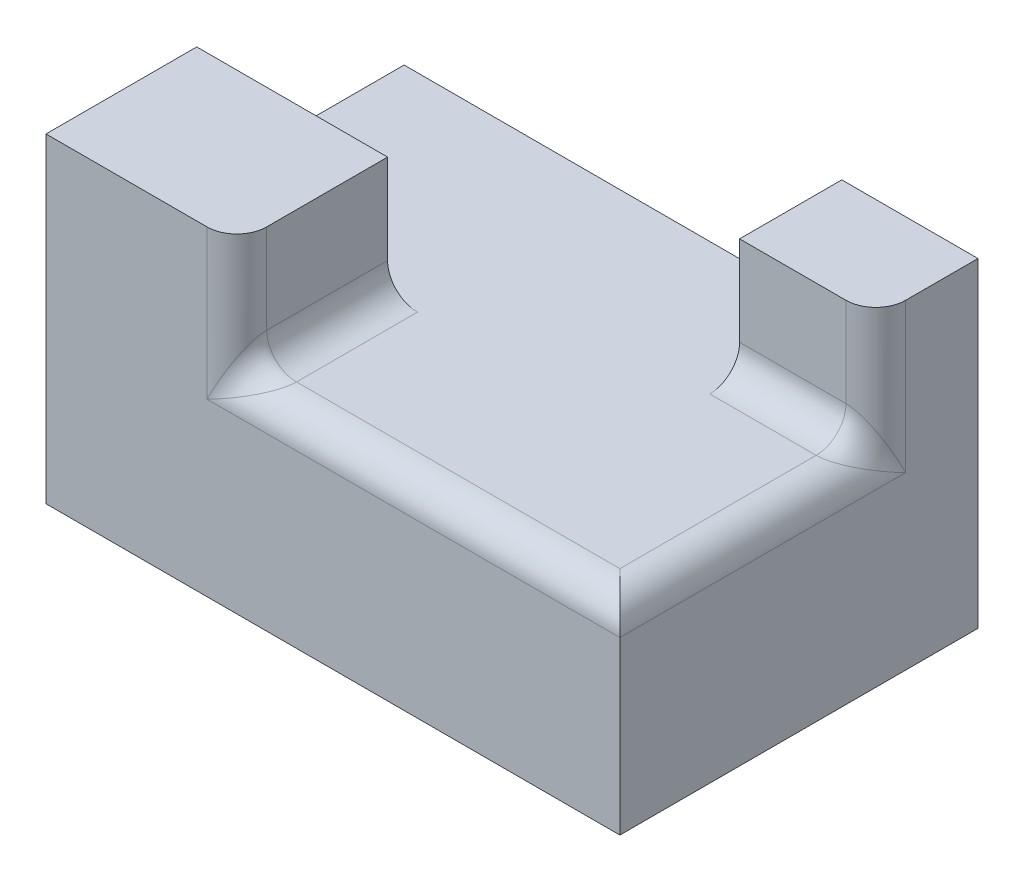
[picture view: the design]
ISO-10303-21;
HEADER;
FILE_DESCRIPTION(('STEP AP214'),'2;1');
FILE_NAME('part.step','',(''),(''),'','','');
FILE_SCHEMA(('AUTOMOTIVE_DESIGN { 1 0 10303 214 1 1 1 1 }'));
ENDSEC;
DATA;
#1=APPLICATION_CONTEXT('core data for automotive mechanical design processes');
#2=APPLICATION_PROTOCOL_DEFINITION('international standard','automotive_design',2000,#1);
#3=PRODUCT_CONTEXT('',#1,'mechanical');
#4=PRODUCT('Part','Part','',(#3));
#5=PRODUCT_RELATED_PRODUCT_CATEGORY('part','',(#4));
#6=PRODUCT_DEFINITION_FORMATION('','',#4);
#7=PRODUCT_DEFINITION_CONTEXT('part definition',#1,'design');
#8=PRODUCT_DEFINITION('design','',#6,#7);
#9=PRODUCT_DEFINITION_SHAPE('','',#8);
#10=(LENGTH_UNIT() NAMED_UNIT(*) SI_UNIT(.MILLI.,.METRE.));
#11=(NAMED_UNIT(*) PLANE_ANGLE_UNIT() SI_UNIT($,.RADIAN.));
#12=(NAMED_UNIT(*) SI_UNIT($,.STERADIAN.) SOLID_ANGLE_UNIT());
#13=UNCERTAINTY_MEASURE_WITH_UNIT(LENGTH_MEASURE(1.E-05),#10,'distance_accuracy_value','');
#14=(GEOMETRIC_REPRESENTATION_CONTEXT(3) GLOBAL_UNCERTAINTY_ASSIGNED_CONTEXT((#13)) GLOBAL_UNIT_ASSIGNED_CONTEXT((#10,
#11,#12)) REPRESENTATION_CONTEXT('',''));
#15=CARTESIAN_POINT('',(0.,0.,0.));
#16=DIRECTION('',(0.,0.,1.));
#17=DIRECTION('',(1.,0.,0.));
#18=AXIS2_PLACEMENT_3D('',#15,#16,#17);
#19=CARTESIAN_POINT('',(96.1490143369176,28.6618279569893,12.1202496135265));
#20=CARTESIAN_POINT('',(96.1490143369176,28.6618279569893,12.1202496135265));
#21=CARTESIAN_POINT('',(96.1490143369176,28.6618279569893,12.1202496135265));
#22=CARTESIAN_POINT('',(96.1490080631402,28.7707616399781,12.3381169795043));
#23=CARTESIAN_POINT('',(96.1490377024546,28.8252281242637,12.283649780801));
#24=CARTESIAN_POINT('',(96.1490080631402,28.879695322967,12.2291832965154));
#25=CARTESIAN_POINT('',(96.1454544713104,28.8796796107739,12.5559529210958));
#26=CARTESIAN_POINT('',(96.1418871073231,28.9887210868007,12.447142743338));
#27=CARTESIAN_POINT('',(96.1454544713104,29.0975312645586,12.3381012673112));
#28=CARTESIAN_POINT('',(96.1312103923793,29.0972907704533,12.9911752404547));
#29=CARTESIAN_POINT('',(96.1134165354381,29.3144399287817,12.772861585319));
#30=CARTESIAN_POINT('',(96.1312103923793,29.5327535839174,12.5557124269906));
#31=CARTESIAN_POINT('',(96.1205193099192,29.2059839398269,13.2085615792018));
#32=CARTESIAN_POINT('',(96.0920548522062,29.4768961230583,12.9353177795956));
#33=CARTESIAN_POINT('',(96.1205193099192,29.7501399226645,12.6644055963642));
#34=CARTESIAN_POINT('',(96.0779288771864,29.5294979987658,13.8555896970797));
#35=CARTESIAN_POINT('',(96.0070926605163,29.958646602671,13.4170682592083));
#36=CARTESIAN_POINT('',(96.0779288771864,30.3971680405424,12.9879196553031));
#37=CARTESIAN_POINT('',(96.0355125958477,29.7436796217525,14.283952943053));
#38=CARTESIAN_POINT('',(95.9223415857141,30.2752082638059,13.7336299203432));
#39=CARTESIAN_POINT('',(96.0355125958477,30.8255312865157,13.2021012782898));
#40=CARTESIAN_POINT('',(95.9227282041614,30.1646067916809,15.1258072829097));
#41=CARTESIAN_POINT('',(95.7008351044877,30.8841688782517,14.342590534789));
#42=CARTESIAN_POINT('',(95.9227282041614,31.6673856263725,13.6230284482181));
#43=CARTESIAN_POINT('',(95.852840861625,30.3714168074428,15.5394273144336));
#44=CARTESIAN_POINT('',(95.5637556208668,31.1783980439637,14.636819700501));
#45=CARTESIAN_POINT('',(95.852840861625,32.0810056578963,13.8298384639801));
#46=CARTESIAN_POINT('',(95.6860629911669,30.7740522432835,16.344698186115));
#47=CARTESIAN_POINT('',(95.244452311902,31.7320304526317,15.190452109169));
#48=CARTESIAN_POINT('',(95.6860629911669,32.8862765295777,14.2324738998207));
#49=CARTESIAN_POINT('',(95.5898800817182,30.9700227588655,16.7366392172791));
#50=CARTESIAN_POINT('',(95.0617453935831,31.9932055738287,15.451627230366));
#51=CARTESIAN_POINT('',(95.5898800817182,33.2782175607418,14.4284444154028));
#52=CARTESIAN_POINT('',(95.3719274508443,31.3475279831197,17.4916496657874));
#53=CARTESIAN_POINT('',(94.661515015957,32.4707340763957,15.9291557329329));
#54=CARTESIAN_POINT('',(95.3719274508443,34.0332280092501,14.805949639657));
#55=CARTESIAN_POINT('',(95.2510696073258,31.5293236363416,17.8552409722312));
#56=CARTESIAN_POINT('',(94.4433664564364,32.6887553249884,16.1471769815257));
#57=CARTESIAN_POINT('',(95.2510696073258,34.3968193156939,14.9877452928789));
#58=CARTESIAN_POINT('',(94.985632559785,31.8752478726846,18.5470894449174));
#59=CARTESIAN_POINT('',(93.9867474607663,33.0715758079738,16.529997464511));
#60=CARTESIAN_POINT('',(94.985632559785,35.0886677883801,15.3336695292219));
#61=CARTESIAN_POINT('',(94.8421290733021,32.0397852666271,18.8761642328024));
#62=CARTESIAN_POINT('',(93.7475519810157,33.2378779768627,16.6962996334));
#63=CARTESIAN_POINT('',(94.8421290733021,35.4177425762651,15.4982069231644));
#64=CARTESIAN_POINT('',(94.5336806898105,32.348225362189,19.4930444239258));
#65=CARTESIAN_POINT('',(93.2679895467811,33.5118870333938,16.9703086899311));
#66=CARTESIAN_POINT('',(94.5336806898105,36.0346227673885,15.8066470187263));
#67=CARTESIAN_POINT('',(94.3699096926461,32.4927085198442,19.7820107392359));
#68=CARTESIAN_POINT('',(93.0268733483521,33.6208675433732,17.0792891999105));
#69=CARTESIAN_POINT('',(94.3699096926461,36.3235890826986,15.9511301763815));
#70=CARTESIAN_POINT('',(94.0236930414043,32.7583729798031,20.3133396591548));
#71=CARTESIAN_POINT('',(92.5666913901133,33.7802352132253,17.2386568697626));
#72=CARTESIAN_POINT('',(94.0236930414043,36.8549180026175,16.2167946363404));
#73=CARTESIAN_POINT('',(93.8424176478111,32.8803097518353,20.5572132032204));
#74=CARTESIAN_POINT('',(92.3469605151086,33.831617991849,17.2900396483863));
#75=CARTESIAN_POINT('',(93.8424176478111,37.0987915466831,16.3387314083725));
#76=CARTESIAN_POINT('',(93.4641525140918,33.0986694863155,20.9939326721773));
#77=CARTESIAN_POINT('',(91.9539994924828,33.8839523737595,17.3423740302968));
#78=CARTESIAN_POINT('',(93.4641525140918,37.53551101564,16.5570911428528));
#79=CARTESIAN_POINT('',(93.2682103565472,33.1959814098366,21.1885565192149));
#80=CARTESIAN_POINT('',(91.7802865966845,33.8856184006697,17.344040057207));
#81=CARTESIAN_POINT('',(93.2682103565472,37.7301348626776,16.6544030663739));
#82=CARTESIAN_POINT('',(92.9634821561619,33.3222155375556,21.4410247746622));
#83=CARTESIAN_POINT('',(91.5679602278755,33.8642822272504,17.3227038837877));
#84=CARTESIAN_POINT('',(92.9634821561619,37.9826031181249,16.7806371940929));
#85=CARTESIAN_POINT('',(92.862258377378,33.3604151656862,21.517424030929));
#86=CARTESIAN_POINT('',(91.5057132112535,33.853419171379,17.3118408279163));
#87=CARTESIAN_POINT('',(92.862258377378,38.0590023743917,16.8188368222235));
#88=CARTESIAN_POINT('',(92.6556569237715,33.430675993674,21.6579456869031));
#89=CARTESIAN_POINT('',(91.3965943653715,33.8268596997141,17.2852813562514));
#90=CARTESIAN_POINT('',(92.6556569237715,38.1995240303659,16.8890976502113));
#91=CARTESIAN_POINT('',(92.5502812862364,33.4627401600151,21.7220740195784));
#92=CARTESIAN_POINT('',(91.3499908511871,33.8111282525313,17.2695499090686));
#93=CARTESIAN_POINT('',(92.5502812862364,38.2636523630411,16.9211618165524));
#94=CARTESIAN_POINT('',(92.3390935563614,33.5193284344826,21.8352505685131));
#95=CARTESIAN_POINT('',(91.2737685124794,33.7785309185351,17.2369525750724));
#96=CARTESIAN_POINT('',(92.3390935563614,38.3768289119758,16.9777500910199));
#97=CARTESIAN_POINT('',(92.2333856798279,33.5440467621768,21.8846872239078));
#98=CARTESIAN_POINT('',(91.2439084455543,33.7617235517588,17.2201452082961));
#99=CARTESIAN_POINT('',(92.2333856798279,38.4262655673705,17.0024684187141));
#100=CARTESIAN_POINT('',(92.0193127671,33.5867119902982,21.9700176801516));
#101=CARTESIAN_POINT('',(91.1978030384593,33.7298203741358,17.1882420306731));
#102=CARTESIAN_POINT('',(92.0193127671,38.5115960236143,17.0451336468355));
#103=CARTESIAN_POINT('',(91.910949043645,33.6046621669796,22.005918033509));
#104=CARTESIAN_POINT('',(91.1817160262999,33.7147753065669,17.1731969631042));
#105=CARTESIAN_POINT('',(91.910949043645,38.5474963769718,17.0630838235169));
#106=CARTESIAN_POINT('',(91.6941005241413,33.6332107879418,22.0630152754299));
#107=CARTESIAN_POINT('',(91.1601582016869,33.6895473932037,17.147969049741));
#108=CARTESIAN_POINT('',(91.6941005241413,38.6045936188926,17.0916324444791));
#109=CARTESIAN_POINT('',(91.5856457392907,33.6439228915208,22.0844394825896));
#110=CARTESIAN_POINT('',(91.1546045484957,33.6793472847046,17.1377689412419));
#111=CARTESIAN_POINT('',(91.5856457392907,38.6260178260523,17.1023445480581));
#112=CARTESIAN_POINT('',(91.3677987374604,33.6582314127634,22.1130565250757));
#113=CARTESIAN_POINT('',(91.1490230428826,33.66546856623,17.1238902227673));
#114=CARTESIAN_POINT('',(91.3677987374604,38.6546348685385,17.1166530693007));
#115=CARTESIAN_POINT('',(91.258406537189,33.6618279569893,22.1202496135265));
#116=CARTESIAN_POINT('',(91.149018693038,33.6618279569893,17.1202496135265));
#117=CARTESIAN_POINT('',(91.258406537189,38.6618279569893,17.1202496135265));
#118=CARTESIAN_POINT('',(91.0396221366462,33.6618279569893,22.1202496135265));
#119=CARTESIAN_POINT('',(91.1490099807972,33.6618279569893,17.1202496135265));
#120=CARTESIAN_POINT('',(91.0396221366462,38.6618279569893,17.1202496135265));
#121=CARTESIAN_POINT('',(90.9302299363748,33.6582314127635,22.1130565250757));
#122=CARTESIAN_POINT('',(91.1490056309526,33.66546856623,17.1238902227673));
#123=CARTESIAN_POINT('',(90.9302299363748,38.6546348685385,17.1166530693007));
#124=CARTESIAN_POINT('',(90.7123829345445,33.6439228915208,22.0844394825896));
#125=CARTESIAN_POINT('',(91.1434241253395,33.6793472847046,17.1377689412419));
#126=CARTESIAN_POINT('',(90.7123829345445,38.6260178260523,17.1023445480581));
#127=CARTESIAN_POINT('',(90.6039281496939,33.6332107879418,22.0630152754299));
#128=CARTESIAN_POINT('',(91.1378704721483,33.6895473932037,17.147969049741));
#129=CARTESIAN_POINT('',(90.6039281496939,38.6045936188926,17.0916324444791));
#130=CARTESIAN_POINT('',(90.3870796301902,33.6046621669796,22.005918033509));
#131=CARTESIAN_POINT('',(91.1163126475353,33.7147753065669,17.1731969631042));
#132=CARTESIAN_POINT('',(90.3870796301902,38.5474963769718,17.0630838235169));
#133=CARTESIAN_POINT('',(90.2787159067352,33.5867119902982,21.9700176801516));
#134=CARTESIAN_POINT('',(91.1002256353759,33.7298203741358,17.1882420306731));
#135=CARTESIAN_POINT('',(90.2787159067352,38.5115960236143,17.0451336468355));
#136=CARTESIAN_POINT('',(90.0646429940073,33.5440467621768,21.8846872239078));
#137=CARTESIAN_POINT('',(91.0541202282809,33.7617235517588,17.2201452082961));
#138=CARTESIAN_POINT('',(90.0646429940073,38.4262655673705,17.0024684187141));
#139=CARTESIAN_POINT('',(89.9589351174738,33.5193284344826,21.8352505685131));
#140=CARTESIAN_POINT('',(91.0242601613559,33.7785309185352,17.2369525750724));
#141=CARTESIAN_POINT('',(89.9589351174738,38.3768289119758,16.9777500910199));
#142=CARTESIAN_POINT('',(89.7477473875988,33.4627401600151,21.7220740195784));
#143=CARTESIAN_POINT('',(90.9480378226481,33.8111282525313,17.2695499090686));
#144=CARTESIAN_POINT('',(89.7477473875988,38.2636523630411,16.9211618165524));
#145=CARTESIAN_POINT('',(89.6423717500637,33.430675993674,21.6579456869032));
#146=CARTESIAN_POINT('',(90.9014343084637,33.8268596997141,17.2852813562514));
#147=CARTESIAN_POINT('',(89.6423717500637,38.1995240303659,16.8890976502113));
#148=CARTESIAN_POINT('',(89.4357702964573,33.3604151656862,21.517424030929));
#149=CARTESIAN_POINT('',(90.7923154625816,33.853419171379,17.3118408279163));
#150=CARTESIAN_POINT('',(89.4357702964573,38.0590023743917,16.8188368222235));
#151=CARTESIAN_POINT('',(89.3345465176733,33.3222155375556,21.4410247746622));
#152=CARTESIAN_POINT('',(90.7300684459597,33.8642822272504,17.3227038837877));
#153=CARTESIAN_POINT('',(89.3345465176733,37.9826031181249,16.7806371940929));
#154=CARTESIAN_POINT('',(89.029818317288,33.1959814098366,21.1885565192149));
#155=CARTESIAN_POINT('',(90.5177420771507,33.8856184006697,17.344040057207));
#156=CARTESIAN_POINT('',(89.029818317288,37.7301348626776,16.6544030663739));
#157=CARTESIAN_POINT('',(88.8338761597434,33.0986694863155,20.9939326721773));
#158=CARTESIAN_POINT('',(90.3440291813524,33.8839523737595,17.3423740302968));
#159=CARTESIAN_POINT('',(88.8338761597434,37.53551101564,16.5570911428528));
#160=CARTESIAN_POINT('',(88.4556110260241,32.8803097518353,20.5572132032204));
#161=CARTESIAN_POINT('',(89.9510681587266,33.831617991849,17.2900396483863));
#162=CARTESIAN_POINT('',(88.4556110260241,37.0987915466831,16.3387314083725));
#163=CARTESIAN_POINT('',(88.2743356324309,32.7583729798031,20.3133396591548));
#164=CARTESIAN_POINT('',(89.7313372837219,33.7802352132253,17.2386568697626));
#165=CARTESIAN_POINT('',(88.2743356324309,36.8549180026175,16.2167946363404));
#166=CARTESIAN_POINT('',(87.9281189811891,32.4927085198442,19.7820107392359));
#167=CARTESIAN_POINT('',(89.2711553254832,33.6208675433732,17.0792891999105));
#168=CARTESIAN_POINT('',(87.9281189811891,36.3235890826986,15.9511301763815));
#169=CARTESIAN_POINT('',(87.7643479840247,32.348225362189,19.4930444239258));
#170=CARTESIAN_POINT('',(89.0300391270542,33.5118870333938,16.9703086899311));
#171=CARTESIAN_POINT('',(87.7643479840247,36.0346227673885,15.8066470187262));
#172=CARTESIAN_POINT('',(87.4558996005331,32.0397852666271,18.8761642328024));
#173=CARTESIAN_POINT('',(88.5504766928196,33.2378779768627,16.6962996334));
#174=CARTESIAN_POINT('',(87.4558996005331,35.4177425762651,15.4982069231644));
#175=CARTESIAN_POINT('',(87.3123961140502,31.8752478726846,18.5470894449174));
#176=CARTESIAN_POINT('',(88.3112812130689,33.0715758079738,16.529997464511));
#177=CARTESIAN_POINT('',(87.3123961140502,35.0886677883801,15.3336695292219));
#178=CARTESIAN_POINT('',(87.0469590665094,31.5293236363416,17.8552409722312));
#179=CARTESIAN_POINT('',(87.8546622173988,32.6887553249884,16.1471769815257));
#180=CARTESIAN_POINT('',(87.0469590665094,34.3968193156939,14.9877452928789));
#181=CARTESIAN_POINT('',(86.9261012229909,31.3475279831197,17.4916496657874));
#182=CARTESIAN_POINT('',(87.6365136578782,32.4707340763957,15.929155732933));
#183=CARTESIAN_POINT('',(86.9261012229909,34.0332280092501,14.805949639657));
#184=CARTESIAN_POINT('',(86.708148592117,30.9700227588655,16.7366392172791));
#185=CARTESIAN_POINT('',(87.2362832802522,31.9932055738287,15.451627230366));
#186=CARTESIAN_POINT('',(86.708148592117,33.2782175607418,14.4284444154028));
#187=CARTESIAN_POINT('',(86.6119656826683,30.7740522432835,16.344698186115));
#188=CARTESIAN_POINT('',(87.0535763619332,31.7320304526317,15.190452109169));
#189=CARTESIAN_POINT('',(86.6119656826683,32.8862765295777,14.2324738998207));
#190=CARTESIAN_POINT('',(86.4451878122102,30.3714168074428,15.5394273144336));
#191=CARTESIAN_POINT('',(86.7342730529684,31.1783980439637,14.636819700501));
#192=CARTESIAN_POINT('',(86.4451878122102,32.0810056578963,13.8298384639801));
#193=CARTESIAN_POINT('',(86.3753004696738,30.1646067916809,15.1258072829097));
#194=CARTESIAN_POINT('',(86.5971935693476,30.8841688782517,14.342590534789));
#195=CARTESIAN_POINT('',(86.3753004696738,31.6673856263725,13.6230284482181));
#196=CARTESIAN_POINT('',(86.2625160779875,29.7436796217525,14.283952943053));
#197=CARTESIAN_POINT('',(86.3756870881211,30.2752082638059,13.7336299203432));
#198=CARTESIAN_POINT('',(86.2625160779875,30.8255312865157,13.2021012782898));
#199=CARTESIAN_POINT('',(86.2200997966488,29.5294979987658,13.8555896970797));
#200=CARTESIAN_POINT('',(86.2909360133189,29.958646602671,13.4170682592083));
#201=CARTESIAN_POINT('',(86.2200997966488,30.3971680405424,12.9879196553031));
#202=CARTESIAN_POINT('',(86.177509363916,29.2059839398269,13.2085615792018));
#203=CARTESIAN_POINT('',(86.205973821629,29.4768961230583,12.9353177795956));
#204=CARTESIAN_POINT('',(86.177509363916,29.7501399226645,12.6644055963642));
#205=CARTESIAN_POINT('',(86.1668182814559,29.0972907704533,12.9911752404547));
#206=CARTESIAN_POINT('',(86.1846121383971,29.3144399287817,12.772861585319));
#207=CARTESIAN_POINT('',(86.1668182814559,29.5327535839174,12.5557124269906));
#208=CARTESIAN_POINT('',(86.1525742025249,28.8796796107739,12.5559529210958));
#209=CARTESIAN_POINT('',(86.156141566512,28.9887210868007,12.447142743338));
#210=CARTESIAN_POINT('',(86.1525742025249,29.0975312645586,12.3381012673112));
#211=CARTESIAN_POINT('',(86.149020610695,28.7707616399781,12.3381169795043));
#212=CARTESIAN_POINT('',(86.1489909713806,28.8252281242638,12.283649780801));
#213=CARTESIAN_POINT('',(86.149020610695,28.879695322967,12.2291832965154));
#214=CARTESIAN_POINT('',(86.1490143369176,28.6618279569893,12.1202496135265));
#215=CARTESIAN_POINT('',(86.1490143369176,28.6618279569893,12.1202496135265));
#216=CARTESIAN_POINT('',(86.1490143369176,28.6618279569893,12.1202496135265));
#217=(BOUNDED_SURFACE() B_SPLINE_SURFACE(3,2,((#19,#20,#21),(#22,#23,#24),(#25,#26,#27),(#28,
#29,#30),(#31,#32,#33),(#34,#35,#36),(#37,#38,#39),(#40,#41,#42),(#43,#44,#45),(#46,#47,#48),
(#49,#50,#51),(#52,#53,#54),(#55,#56,#57),(#58,#59,#60),(#61,#62,#63),(#64,#65,#66),(#67,#68,
#69),(#70,#71,#72),(#73,#74,#75),(#76,#77,#78),(#79,#80,#81),(#82,#83,#84),(#85,#86,#87),(#88,
#89,#90),(#91,#92,#93),(#94,#95,#96),(#97,#98,#99),(#100,#101,#102),(#103,#104,#105),(#106,#107,
#108),(#109,#110,#111),(#112,#113,#114),(#115,#116,#117),(#118,#119,#120),(#121,#122,#123),
(#124,#125,#126),(#127,#128,#129),(#130,#131,#132),(#133,#134,#135),(#136,#137,#138),(#139,#140,
#141),(#142,#143,#144),(#145,#146,#147),(#148,#149,#150),(#151,#152,#153),(#154,#155,#156),
(#157,#158,#159),(#160,#161,#162),(#163,#164,#165),(#166,#167,#168),(#169,#170,#171),(#172,#173,
#174),(#175,#176,#177),(#178,#179,#180),(#181,#182,#183),(#184,#185,#186),(#187,#188,#189),
(#190,#191,#192),(#193,#194,#195),(#196,#197,#198),(#199,#200,#201),(#202,#203,#204),(#205,#206,
#207),(#208,#209,#210),(#211,#212,#213),(#214,#215,#216)),.UNSPECIFIED.,.F.,.F.,
.F.) B_SPLINE_SURFACE_WITH_KNOTS((4,2,2,2,2,2,2,2,2,2,2,2,2,2,2,2,2,2,2,2,2,2,2,2,2,2,2,2,2,2,2,
2,4),(3,3),(0.,0.924160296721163,1.84839768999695,3.68059127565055,5.48205356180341,
7.23913791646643,8.94029416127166,10.5768174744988,12.1436214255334,13.6400005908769,
15.0702934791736,15.7580538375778,16.4454808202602,17.1126662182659,17.7795282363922,
18.4356587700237,19.0917776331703,19.7478964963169,20.4040270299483,21.0708890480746,
21.7380744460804,22.4255014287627,23.1132617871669,24.5435546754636,26.0399338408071,
27.6067377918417,29.2432611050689,30.9444173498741,32.7015017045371,34.50296399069,
36.3351575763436,37.2593949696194,38.1835552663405),(0.,1.),
.UNSPECIFIED.) GEOMETRIC_REPRESENTATION_ITEM() RATIONAL_B_SPLINE_SURFACE(((1.,1.,1.),(1.,
0.999999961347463,1.),(1.,0.999643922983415,1.),(1.,0.998220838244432,1.),(1.,0.9971537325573,
1.),(1.,0.992912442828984,1.),(1.,0.988698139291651,1.),(1.,0.97761667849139,1.),(1.,
0.970795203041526,1.),(1.,0.954789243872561,1.),(1.,0.945667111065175,1.),(1.,0.925487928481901,
1.),(1.,0.914501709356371,1.),(1.,0.891170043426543,1.),(1.,0.878892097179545,1.),(1.,
0.853706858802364,1.),(1.,0.840848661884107,1.),(1.,0.815387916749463,1.),(1.,0.802799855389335,
1.),(1.,0.778879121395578,1.),(1.,0.767515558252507,1.),(1.,0.752114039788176,1.),(1.,
0.747335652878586,1.),(1.,0.738380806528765,1.),(1.,0.734204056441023,1.),(1.,0.726720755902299,
1.),(1.,0.723392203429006,1.),(1.,0.717584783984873,1.),(1.,0.715105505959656,1.),(1.,
0.711136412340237,1.),(1.,0.709631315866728,1.),(1.,0.70761650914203,1.),(1.,0.707106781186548,
1.),(1.,0.707106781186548,1.),(1.,0.70761650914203,1.),(1.,0.709631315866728,1.),(1.,
0.711136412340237,1.),(1.,0.715105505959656,1.),(1.,0.717584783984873,1.),(1.,0.723392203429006,
1.),(1.,0.726720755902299,1.),(1.,0.734204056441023,1.),(1.,0.738380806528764,1.),(1.,
0.747335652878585,1.),(1.,0.752114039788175,1.),(1.,0.767515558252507,1.),(1.,0.778879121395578,
1.),(1.,0.802799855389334,1.),(1.,0.815387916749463,1.),(1.,0.840848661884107,1.),(1.,
0.853706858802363,1.),(1.,0.878892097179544,1.),(1.,0.891170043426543,1.),(1.,0.914501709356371,
1.),(1.,0.925487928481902,1.),(1.,0.945667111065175,1.),(1.,0.954789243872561,1.),(1.,
0.970795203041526,1.),(1.,0.97761667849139,1.),(1.,0.988698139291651,1.),(1.,0.992912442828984,
1.),(1.,0.9971537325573,1.),(1.,0.998220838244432,1.),(1.,0.999643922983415,1.),(1.,
0.999999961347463,1.),(1.,1.,1.))) REPRESENTATION_ITEM('') SURFACE());
#218=CARTESIAN_POINT('',(91.1490143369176,38.6618279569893,22.1202496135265));
#219=DIRECTION('',(-1.,0.,0.));
#220=DIRECTION('',(0.,0.,1.));
#221=AXIS2_PLACEMENT_3D('',#218,#219,#220);
#222=CIRCLE('',#221,5.);
#223=CARTESIAN_POINT('',(91.1490143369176,38.6618279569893,17.1202496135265));
#224=VERTEX_POINT('',#223);
#225=CARTESIAN_POINT('',(91.1490143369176,33.6618279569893,22.1202496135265));
#226=VERTEX_POINT('',#225);
#227=EDGE_CURVE('E103',#224,#226,#222,.T.);
#228=ORIENTED_EDGE('',*,*,#227,.T.);
#229=CARTESIAN_POINT('',(91.1490143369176,28.6618279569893,12.1202496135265));
#230=DIRECTION('',(0.,0.894427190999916,-0.447213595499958));
#231=DIRECTION('',(0.,-0.447213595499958,-0.894427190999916));
#232=AXIS2_PLACEMENT_3D('',#229,#230,#231);
#233=ELLIPSE('',#232,11.1803398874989,5.);
#234=CARTESIAN_POINT('',(96.1490143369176,28.6618279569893,12.1202496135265));
#235=VERTEX_POINT('',#234);
#236=EDGE_CURVE('E109',#235,#226,#233,.F.);
#237=ORIENTED_EDGE('',*,*,#236,.F.);
#238=CARTESIAN_POINT('',(91.1490143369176,28.6618279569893,12.1202496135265));
#239=DIRECTION('',(0.,0.447213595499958,-0.894427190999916));
#240=DIRECTION('',(0.,-0.894427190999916,-0.447213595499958));
#241=AXIS2_PLACEMENT_3D('',#238,#239,#240);
#242=ELLIPSE('',#241,11.1803398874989,5.);
#243=EDGE_CURVE('E115',#224,#235,#242,.T.);
#244=ORIENTED_EDGE('',*,*,#243,.F.);
#245=EDGE_LOOP('',(#228,#237,#244));
#246=FACE_BOUND('',#245,.T.);
#247=ADVANCED_FACE('F32',(#246),#217,.F.);
#248=CARTESIAN_POINT('',(0.,33.6618279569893,60.));
#249=DIRECTION('',(0.,-1.,0.));
#250=DIRECTION('',(0.,0.,-1.));
#251=AXIS2_PLACEMENT_3D('',#248,#249,#250);
#252=PLANE('',#251);
#253=DIRECTION('',(0.,0.,-1.));
#254=VECTOR('',#253,1.);
#255=CARTESIAN_POINT('',(91.1490143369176,33.6618279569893,60.));
#256=LINE('',#255,#254);
#257=CARTESIAN_POINT('',(91.1490143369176,33.6618279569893,55.));
#258=VERTEX_POINT('',#257);
#259=EDGE_CURVE('E83',#258,#226,#256,.T.);
#260=ORIENTED_EDGE('',*,*,#259,.T.);
#261=DIRECTION('',(1.,0.,0.));
#262=VECTOR('',#261,1.);
#263=CARTESIAN_POINT('',(73.3247964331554,33.6618279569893,22.1202496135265));
#264=LINE('',#263,#262);
#265=CARTESIAN_POINT('',(73.3247964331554,33.6618279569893,22.1202496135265));
#266=VERTEX_POINT('',#265);
#267=EDGE_CURVE('E88',#226,#266,#264,.F.);
#268=ORIENTED_EDGE('',*,*,#267,.T.);
#269=DIRECTION('',(0.,0.,1.));
#270=VECTOR('',#269,1.);
#271=CARTESIAN_POINT('',(73.3247964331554,33.6618279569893,0.));
#272=LINE('',#271,#270);
#273=CARTESIAN_POINT('',(73.3247964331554,33.6618279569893,0.));
#274=VERTEX_POINT('',#273);
#275=EDGE_CURVE('E213',#274,#266,#272,.T.);
#276=ORIENTED_EDGE('',*,*,#275,.F.);
#277=DIRECTION('',(-1.,0.,0.));
#278=VECTOR('',#277,1.);
#279=CARTESIAN_POINT('',(0.,33.6618279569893,0.));
#280=LINE('',#279,#278);
#281=CARTESIAN_POINT('',(0.,33.6618279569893,0.));
#282=VERTEX_POINT('',#281);
#283=EDGE_CURVE('E355',#274,#282,#280,.T.);
#284=ORIENTED_EDGE('',*,*,#283,.T.);
#285=DIRECTION('',(0.,0.,-1.));
#286=VECTOR('',#285,1.);
#287=CARTESIAN_POINT('',(0.,33.6618279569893,60.));
#288=LINE('',#287,#286);
#289=CARTESIAN_POINT('',(0.,33.6618279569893,34.7454000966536));
#290=VERTEX_POINT('',#289);
#291=EDGE_CURVE('E250',#290,#282,#288,.T.);
#292=ORIENTED_EDGE('',*,*,#291,.F.);
#293=DIRECTION('',(-1.,0.,0.));
#294=VECTOR('',#293,1.);
#295=CARTESIAN_POINT('',(0.,33.6618279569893,34.7454000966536));
#296=LINE('',#295,#294);
#297=CARTESIAN_POINT('',(36.9746669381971,33.6618279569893,34.7454000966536));
#298=VERTEX_POINT('',#297);
#299=EDGE_CURVE('E228',#298,#290,#296,.T.);
#300=ORIENTED_EDGE('',*,*,#299,.F.);
#301=DIRECTION('',(0.,0.,-1.));
#302=VECTOR('',#301,1.);
#303=CARTESIAN_POINT('',(36.9746669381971,33.6618279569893,60.));
#304=LINE('',#303,#302);
#305=CARTESIAN_POINT('',(36.9746669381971,33.6618279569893,55.));
#306=VERTEX_POINT('',#305);
#307=EDGE_CURVE('E264',#298,#306,#304,.F.);
#308=ORIENTED_EDGE('',*,*,#307,.T.);
#309=DIRECTION('',(-1.,0.,0.));
#310=VECTOR('',#309,1.);
#311=CARTESIAN_POINT('',(0.,33.6618279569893,55.));
#312=LINE('',#311,#310);
#313=EDGE_CURVE('E91',#306,#258,#312,.F.);
#314=ORIENTED_EDGE('',*,*,#313,.T.);
#315=EDGE_LOOP('',(#260,#268,#276,#284,#292,#300,#308,#314));
#316=FACE_BOUND('',#315,.T.);
#317=ADVANCED_FACE('F85',(#316),#252,.F.);
#318=CARTESIAN_POINT('',(0.,0.,60.));
#319=DIRECTION('',(1.,0.,0.));
#320=DIRECTION('',(0.,0.,-1.));
#321=AXIS2_PLACEMENT_3D('',#318,#319,#320);
#322=PLANE('',#321);
#323=DIRECTION('',(0.,-1.,0.));
#324=VECTOR('',#323,1.);
#325=CARTESIAN_POINT('',(0.,0.,0.));
#326=LINE('',#325,#324);
#327=CARTESIAN_POINT('',(0.,0.,0.));
#328=VERTEX_POINT('',#327);
#329=EDGE_CURVE('E340',#282,#328,#326,.T.);
#330=ORIENTED_EDGE('',*,*,#329,.T.);
#331=DIRECTION('',(0.,0.,-1.));
#332=VECTOR('',#331,1.);
#333=CARTESIAN_POINT('',(0.,0.,60.));
#334=LINE('',#333,#332);
#335=CARTESIAN_POINT('',(0.,0.,60.));
#336=VERTEX_POINT('',#335);
#337=EDGE_CURVE('E260',#336,#328,#334,.T.);
#338=ORIENTED_EDGE('',*,*,#337,.F.);
#339=DIRECTION('',(0.,-1.,0.));
#340=VECTOR('',#339,1.);
#341=CARTESIAN_POINT('',(0.,0.,60.));
#342=LINE('',#341,#340);
#343=CARTESIAN_POINT('',(0.,53.6618279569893,60.));
#344=VERTEX_POINT('',#343);
#345=EDGE_CURVE('E356',#344,#336,#342,.T.);
#346=ORIENTED_EDGE('',*,*,#345,.F.);
#347=DIRECTION('',(0.,0.,1.));
#348=VECTOR('',#347,1.);
#349=CARTESIAN_POINT('',(0.,53.6618279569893,60.));
#350=LINE('',#349,#348);
#351=CARTESIAN_POINT('',(0.,53.6618279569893,34.7454000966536));
#352=VERTEX_POINT('',#351);
#353=EDGE_CURVE('E229',#352,#344,#350,.T.);
#354=ORIENTED_EDGE('',*,*,#353,.F.);
#355=DIRECTION('',(0.,-1.,0.));
#356=VECTOR('',#355,1.);
#357=CARTESIAN_POINT('',(0.,53.6618279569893,34.7454000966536));
#358=LINE('',#357,#356);
#359=EDGE_CURVE('E241',#352,#290,#358,.T.);
#360=ORIENTED_EDGE('',*,*,#359,.T.);
#361=ORIENTED_EDGE('',*,*,#291,.T.);
#362=EDGE_LOOP('',(#330,#338,#346,#354,#360,#361));
#363=FACE_BOUND('',#362,.T.);
#364=ADVANCED_FACE('F141',(#363),#322,.F.);
#365=CARTESIAN_POINT('',(0.,0.,60.));
#366=DIRECTION('',(0.,1.,0.));
#367=DIRECTION('',(0.,0.,1.));
#368=AXIS2_PLACEMENT_3D('',#365,#366,#367);
#369=PLANE('',#368);
#370=DIRECTION('',(1.,0.,0.));
#371=VECTOR('',#370,1.);
#372=CARTESIAN_POINT('',(0.,0.,0.));
#373=LINE('',#372,#371);
#374=CARTESIAN_POINT('',(96.1490143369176,0.,0.));
#375=VERTEX_POINT('',#374);
#376=EDGE_CURVE('E342',#328,#375,#373,.T.);
#377=ORIENTED_EDGE('',*,*,#376,.T.);
#378=DIRECTION('',(0.,0.,-1.));
#379=VECTOR('',#378,1.);
#380=CARTESIAN_POINT('',(96.1490143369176,0.,60.));
#381=LINE('',#380,#379);
#382=CARTESIAN_POINT('',(96.1490143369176,0.,60.));
#383=VERTEX_POINT('',#382);
#384=EDGE_CURVE('E359',#383,#375,#381,.T.);
#385=ORIENTED_EDGE('',*,*,#384,.F.);
#386=DIRECTION('',(1.,0.,0.));
#387=VECTOR('',#386,1.);
#388=CARTESIAN_POINT('',(0.,0.,60.));
#389=LINE('',#388,#387);
#390=EDGE_CURVE('E363',#336,#383,#389,.T.);
#391=ORIENTED_EDGE('',*,*,#390,.F.);
#392=ORIENTED_EDGE('',*,*,#337,.T.);
#393=EDGE_LOOP('',(#377,#385,#391,#392));
#394=FACE_BOUND('',#393,.T.);
#395=ADVANCED_FACE('F144',(#394),#369,.F.);
#396=CARTESIAN_POINT('',(96.1490143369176,0.,60.));
#397=DIRECTION('',(-1.,0.,0.));
#398=DIRECTION('',(0.,0.,1.));
#399=AXIS2_PLACEMENT_3D('',#396,#397,#398);
#400=PLANE('',#399);
#401=DIRECTION('',(0.,-1.,0.));
#402=VECTOR('',#401,1.);
#403=CARTESIAN_POINT('',(96.1490143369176,0.,12.1202496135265));
#404=LINE('',#403,#402);
#405=CARTESIAN_POINT('',(96.1490143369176,53.6618279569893,12.1202496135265));
#406=VERTEX_POINT('',#405);
#407=EDGE_CURVE('E96',#406,#235,#404,.T.);
#408=ORIENTED_EDGE('',*,*,#407,.T.);
#409=DIRECTION('',(0.,0.,-1.));
#410=VECTOR('',#409,1.);
#411=CARTESIAN_POINT('',(96.1490143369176,28.6618279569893,60.));
#412=LINE('',#411,#410);
#413=CARTESIAN_POINT('',(96.1490143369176,28.6618279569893,60.));
#414=VERTEX_POINT('',#413);
#415=EDGE_CURVE('E112',#235,#414,#412,.F.);
#416=ORIENTED_EDGE('',*,*,#415,.T.);
#417=DIRECTION('',(0.,1.,0.));
#418=VECTOR('',#417,1.);
#419=CARTESIAN_POINT('',(96.1490143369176,0.,60.));
#420=LINE('',#419,#418);
#421=EDGE_CURVE('E350',#383,#414,#420,.T.);
#422=ORIENTED_EDGE('',*,*,#421,.F.);
#423=ORIENTED_EDGE('',*,*,#384,.T.);
#424=DIRECTION('',(0.,1.,0.));
#425=VECTOR('',#424,1.);
#426=CARTESIAN_POINT('',(96.1490143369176,0.,0.));
#427=LINE('',#426,#425);
#428=CARTESIAN_POINT('',(96.1490143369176,53.6618279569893,0.));
#429=VERTEX_POINT('',#428);
#430=EDGE_CURVE('E347',#375,#429,#427,.T.);
#431=ORIENTED_EDGE('',*,*,#430,.T.);
#432=DIRECTION('',(0.,0.,-1.));
#433=VECTOR('',#432,1.);
#434=CARTESIAN_POINT('',(96.1490143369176,53.6618279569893,0.));
#435=LINE('',#434,#433);
#436=EDGE_CURVE('E218',#406,#429,#435,.T.);
#437=ORIENTED_EDGE('',*,*,#436,.F.);
#438=EDGE_LOOP('',(#408,#416,#422,#423,#431,#437));
#439=FACE_BOUND('',#438,.T.);
#440=ADVANCED_FACE('F148',(#439),#400,.F.);
#441=CARTESIAN_POINT('',(0.,33.6618279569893,60.));
#442=DIRECTION('',(0.,0.,-1.));
#443=DIRECTION('',(-1.,0.,0.));
#444=AXIS2_PLACEMENT_3D('',#441,#442,#443);
#445=PLANE('',#444);
#446=DIRECTION('',(-1.,0.,0.));
#447=VECTOR('',#446,1.);
#448=CARTESIAN_POINT('',(0.,28.6618279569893,60.));
#449=LINE('',#448,#447);
#450=CARTESIAN_POINT('',(26.9746669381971,28.6618279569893,60.));
#451=VERTEX_POINT('',#450);
#452=EDGE_CURVE('E269',#414,#451,#449,.T.);
#453=ORIENTED_EDGE('',*,*,#452,.T.);
#454=DIRECTION('',(0.,-1.,0.));
#455=VECTOR('',#454,1.);
#456=CARTESIAN_POINT('',(26.9746669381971,33.6618279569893,60.));
#457=LINE('',#456,#455);
#458=CARTESIAN_POINT('',(26.9746669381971,53.6618279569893,60.));
#459=VERTEX_POINT('',#458);
#460=EDGE_CURVE('E266',#451,#459,#457,.F.);
#461=ORIENTED_EDGE('',*,*,#460,.T.);
#462=DIRECTION('',(1.,0.,0.));
#463=VECTOR('',#462,1.);
#464=CARTESIAN_POINT('',(0.,53.6618279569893,60.));
#465=LINE('',#464,#463);
#466=EDGE_CURVE('E232',#344,#459,#465,.T.);
#467=ORIENTED_EDGE('',*,*,#466,.F.);
#468=ORIENTED_EDGE('',*,*,#345,.T.);
#469=ORIENTED_EDGE('',*,*,#390,.T.);
#470=ORIENTED_EDGE('',*,*,#421,.T.);
#471=EDGE_LOOP('',(#453,#461,#467,#468,#469,#470));
#472=FACE_BOUND('',#471,.T.);
#473=ADVANCED_FACE('F152',(#472),#445,.F.);
#474=CARTESIAN_POINT('',(0.,33.6618279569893,0.));
#475=DIRECTION('',(0.,0.,-1.));
#476=DIRECTION('',(-1.,0.,0.));
#477=AXIS2_PLACEMENT_3D('',#474,#475,#476);
#478=PLANE('',#477);
#479=ORIENTED_EDGE('',*,*,#329,.F.);
#480=ORIENTED_EDGE('',*,*,#283,.F.);
#481=DIRECTION('',(0.,-1.,0.));
#482=VECTOR('',#481,1.);
#483=CARTESIAN_POINT('',(73.3247964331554,53.6618279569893,0.));
#484=LINE('',#483,#482);
#485=CARTESIAN_POINT('',(73.3247964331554,53.6618279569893,0.));
#486=VERTEX_POINT('',#485);
#487=EDGE_CURVE('E226',#486,#274,#484,.T.);
#488=ORIENTED_EDGE('',*,*,#487,.F.);
#489=DIRECTION('',(-1.,0.,0.));
#490=VECTOR('',#489,1.);
#491=CARTESIAN_POINT('',(96.1490143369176,53.6618279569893,0.));
#492=LINE('',#491,#490);
#493=EDGE_CURVE('E221',#429,#486,#492,.T.);
#494=ORIENTED_EDGE('',*,*,#493,.F.);
#495=ORIENTED_EDGE('',*,*,#430,.F.);
#496=ORIENTED_EDGE('',*,*,#376,.F.);
#497=EDGE_LOOP('',(#479,#480,#488,#494,#495,#496));
#498=FACE_BOUND('',#497,.T.);
#499=ADVANCED_FACE('F156',(#498),#478,.T.);
#500=CARTESIAN_POINT('',(31.9746669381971,53.6618279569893,60.));
#501=DIRECTION('',(-1.,0.,0.));
#502=DIRECTION('',(0.,0.,1.));
#503=AXIS2_PLACEMENT_3D('',#500,#501,#502);
#504=PLANE('',#503);
#505=DIRECTION('',(0.,-1.,0.));
#506=VECTOR('',#505,1.);
#507=CARTESIAN_POINT('',(31.9746669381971,53.6618279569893,55.));
#508=LINE('',#507,#506);
#509=CARTESIAN_POINT('',(31.9746669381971,53.6618279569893,55.));
#510=VERTEX_POINT('',#509);
#511=CARTESIAN_POINT('',(31.9746669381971,38.6618279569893,55.));
#512=VERTEX_POINT('',#511);
#513=EDGE_CURVE('E257',#510,#512,#508,.T.);
#514=ORIENTED_EDGE('',*,*,#513,.T.);
#515=DIRECTION('',(0.,0.,-1.));
#516=VECTOR('',#515,1.);
#517=CARTESIAN_POINT('',(31.9746669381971,38.6618279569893,34.7454000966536));
#518=LINE('',#517,#516);
#519=CARTESIAN_POINT('',(31.9746669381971,38.6618279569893,34.7454000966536));
#520=VERTEX_POINT('',#519);
#521=EDGE_CURVE('E259',#512,#520,#518,.T.);
#522=ORIENTED_EDGE('',*,*,#521,.T.);
#523=DIRECTION('',(0.,-1.,0.));
#524=VECTOR('',#523,1.);
#525=CARTESIAN_POINT('',(31.9746669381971,53.6618279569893,34.7454000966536));
#526=LINE('',#525,#524);
#527=CARTESIAN_POINT('',(31.9746669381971,53.6618279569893,34.7454000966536));
#528=VERTEX_POINT('',#527);
#529=EDGE_CURVE('E244',#528,#520,#526,.T.);
#530=ORIENTED_EDGE('',*,*,#529,.F.);
#531=DIRECTION('',(0.,0.,-1.));
#532=VECTOR('',#531,1.);
#533=CARTESIAN_POINT('',(31.9746669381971,53.6618279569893,60.));
#534=LINE('',#533,#532);
#535=EDGE_CURVE('E235',#510,#528,#534,.T.);
#536=ORIENTED_EDGE('',*,*,#535,.F.);
#537=EDGE_LOOP('',(#514,#522,#530,#536));
#538=FACE_BOUND('',#537,.T.);
#539=ADVANCED_FACE('F159',(#538),#504,.F.);
#540=CARTESIAN_POINT('',(0.,53.6618279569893,34.7454000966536));
#541=DIRECTION('',(0.,0.,1.));
#542=DIRECTION('',(1.,0.,0.));
#543=AXIS2_PLACEMENT_3D('',#540,#541,#542);
#544=PLANE('',#543);
#545=ORIENTED_EDGE('',*,*,#299,.T.);
#546=ORIENTED_EDGE('',*,*,#359,.F.);
#547=DIRECTION('',(-1.,0.,0.));
#548=VECTOR('',#547,1.);
#549=CARTESIAN_POINT('',(0.,53.6618279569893,34.7454000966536));
#550=LINE('',#549,#548);
#551=EDGE_CURVE('E238',#528,#352,#550,.T.);
#552=ORIENTED_EDGE('',*,*,#551,.F.);
#553=ORIENTED_EDGE('',*,*,#529,.T.);
#554=CARTESIAN_POINT('',(36.9746669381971,38.6618279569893,34.7454000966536));
#555=DIRECTION('',(0.,0.,1.));
#556=DIRECTION('',(1.,0.,0.));
#557=AXIS2_PLACEMENT_3D('',#554,#555,#556);
#558=CIRCLE('',#557,5.);
#559=EDGE_CURVE('E105',#520,#298,#558,.T.);
#560=ORIENTED_EDGE('',*,*,#559,.T.);
#561=EDGE_LOOP('',(#545,#546,#552,#553,#560));
#562=FACE_BOUND('',#561,.T.);
#563=ADVANCED_FACE('F166',(#562),#544,.F.);
#564=CARTESIAN_POINT('',(0.,53.6618279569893,34.7454000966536));
#565=DIRECTION('',(0.,-1.,0.));
#566=DIRECTION('',(0.,0.,-1.));
#567=AXIS2_PLACEMENT_3D('',#564,#565,#566);
#568=PLANE('',#567);
#569=ORIENTED_EDGE('',*,*,#466,.T.);
#570=CARTESIAN_POINT('',(26.9746669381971,53.6618279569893,55.));
#571=DIRECTION('',(0.,-1.,0.));
#572=DIRECTION('',(0.,0.,-1.));
#573=AXIS2_PLACEMENT_3D('',#570,#571,#572);
#574=CIRCLE('',#573,5.);
#575=EDGE_CURVE('E271',#459,#510,#574,.F.);
#576=ORIENTED_EDGE('',*,*,#575,.T.);
#577=ORIENTED_EDGE('',*,*,#535,.T.);
#578=ORIENTED_EDGE('',*,*,#551,.T.);
#579=ORIENTED_EDGE('',*,*,#353,.T.);
#580=EDGE_LOOP('',(#569,#576,#577,#578,#579));
#581=FACE_BOUND('',#580,.T.);
#582=ADVANCED_FACE('F170',(#581),#568,.F.);
#583=CARTESIAN_POINT('',(73.3247964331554,53.6618279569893,0.));
#584=DIRECTION('',(1.,0.,0.));
#585=DIRECTION('',(0.,0.,-1.));
#586=AXIS2_PLACEMENT_3D('',#583,#584,#585);
#587=PLANE('',#586);
#588=ORIENTED_EDGE('',*,*,#275,.T.);
#589=CARTESIAN_POINT('',(73.3247964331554,38.6618279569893,22.1202496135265));
#590=DIRECTION('',(1.,0.,0.));
#591=DIRECTION('',(0.,0.,-1.));
#592=AXIS2_PLACEMENT_3D('',#589,#590,#591);
#593=CIRCLE('',#592,5.);
#594=CARTESIAN_POINT('',(73.3247964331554,38.6618279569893,17.1202496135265));
#595=VERTEX_POINT('',#594);
#596=EDGE_CURVE('E11',#266,#595,#593,.T.);
#597=ORIENTED_EDGE('',*,*,#596,.T.);
#598=DIRECTION('',(0.,-1.,0.));
#599=VECTOR('',#598,1.);
#600=CARTESIAN_POINT('',(73.3247964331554,53.6618279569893,17.1202496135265));
#601=LINE('',#600,#599);
#602=CARTESIAN_POINT('',(73.3247964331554,53.6618279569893,17.1202496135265));
#603=VERTEX_POINT('',#602);
#604=EDGE_CURVE('E200',#603,#595,#601,.T.);
#605=ORIENTED_EDGE('',*,*,#604,.F.);
#606=DIRECTION('',(0.,0.,1.));
#607=VECTOR('',#606,1.);
#608=CARTESIAN_POINT('',(73.3247964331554,53.6618279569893,0.));
#609=LINE('',#608,#607);
#610=EDGE_CURVE('E199',#486,#603,#609,.T.);
#611=ORIENTED_EDGE('',*,*,#610,.F.);
#612=ORIENTED_EDGE('',*,*,#487,.T.);
#613=EDGE_LOOP('',(#588,#597,#605,#611,#612));
#614=FACE_BOUND('',#613,.T.);
#615=ADVANCED_FACE('F174',(#614),#587,.F.);
#616=CARTESIAN_POINT('',(96.1490143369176,53.6618279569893,17.1202496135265));
#617=DIRECTION('',(0.,0.,-1.));
#618=DIRECTION('',(-1.,0.,0.));
#619=AXIS2_PLACEMENT_3D('',#616,#617,#618);
#620=PLANE('',#619);
#621=DIRECTION('',(1.,0.,0.));
#622=VECTOR('',#621,1.);
#623=CARTESIAN_POINT('',(96.1490143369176,38.6618279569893,17.1202496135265));
#624=LINE('',#623,#622);
#625=EDGE_CURVE('E204',#595,#224,#624,.T.);
#626=ORIENTED_EDGE('',*,*,#625,.T.);
#627=DIRECTION('',(0.,-1.,0.));
#628=VECTOR('',#627,1.);
#629=CARTESIAN_POINT('',(91.1490143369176,53.6618279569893,17.1202496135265));
#630=LINE('',#629,#628);
#631=CARTESIAN_POINT('',(91.1490143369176,53.6618279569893,17.1202496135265));
#632=VERTEX_POINT('',#631);
#633=EDGE_CURVE('E76',#224,#632,#630,.F.);
#634=ORIENTED_EDGE('',*,*,#633,.T.);
#635=DIRECTION('',(1.,0.,0.));
#636=VECTOR('',#635,1.);
#637=CARTESIAN_POINT('',(96.1490143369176,53.6618279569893,17.1202496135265));
#638=LINE('',#637,#636);
#639=EDGE_CURVE('E193',#603,#632,#638,.T.);
#640=ORIENTED_EDGE('',*,*,#639,.F.);
#641=ORIENTED_EDGE('',*,*,#604,.T.);
#642=EDGE_LOOP('',(#626,#634,#640,#641));
#643=FACE_BOUND('',#642,.T.);
#644=ADVANCED_FACE('F178',(#643),#620,.F.);
#645=CARTESIAN_POINT('',(96.1490143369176,53.6618279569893,17.1202496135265));
#646=DIRECTION('',(0.,-1.,0.));
#647=DIRECTION('',(0.,0.,-1.));
#648=AXIS2_PLACEMENT_3D('',#645,#646,#647);
#649=PLANE('',#648);
#650=ORIENTED_EDGE('',*,*,#639,.T.);
#651=CARTESIAN_POINT('',(91.1490143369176,53.6618279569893,12.1202496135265));
#652=DIRECTION('',(0.,-1.,0.));
#653=DIRECTION('',(0.,0.,-1.));
#654=AXIS2_PLACEMENT_3D('',#651,#652,#653);
#655=CIRCLE('',#654,5.);
#656=EDGE_CURVE('E45',#632,#406,#655,.F.);
#657=ORIENTED_EDGE('',*,*,#656,.T.);
#658=ORIENTED_EDGE('',*,*,#436,.T.);
#659=ORIENTED_EDGE('',*,*,#493,.T.);
#660=ORIENTED_EDGE('',*,*,#610,.T.);
#661=EDGE_LOOP('',(#650,#657,#658,#659,#660));
#662=FACE_BOUND('',#661,.T.);
#663=ADVANCED_FACE('F181',(#662),#649,.F.);
#664=CARTESIAN_POINT('',(0.,28.6618279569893,55.));
#665=DIRECTION('',(-1.,0.,0.));
#666=DIRECTION('',(0.,0.,1.));
#667=AXIS2_PLACEMENT_3D('',#664,#665,#666);
#668=CYLINDRICAL_SURFACE('',#667,5.);
#669=ORIENTED_EDGE('',*,*,#313,.F.);
#670=CARTESIAN_POINT('',(26.9746669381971,28.6618279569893,55.));
#671=DIRECTION('',(0.447213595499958,-0.894427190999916,0.));
#672=DIRECTION('',(-0.894427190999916,-0.447213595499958,0.));
#673=AXIS2_PLACEMENT_3D('',#670,#671,#672);
#674=ELLIPSE('',#673,11.1803398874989,5.);
#675=EDGE_CURVE('E209',#306,#451,#674,.T.);
#676=ORIENTED_EDGE('',*,*,#675,.T.);
#677=ORIENTED_EDGE('',*,*,#452,.F.);
#678=CARTESIAN_POINT('',(91.1490143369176,28.6618279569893,55.));
#679=DIRECTION('',(-0.707106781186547,0.,0.707106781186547));
#680=DIRECTION('',(-0.707106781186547,0.,-0.707106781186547));
#681=AXIS2_PLACEMENT_3D('',#678,#679,#680);
#682=ELLIPSE('',#681,7.07106781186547,5.);
#683=EDGE_CURVE('E278',#414,#258,#682,.T.);
#684=ORIENTED_EDGE('',*,*,#683,.T.);
#685=EDGE_LOOP('',(#669,#676,#677,#684));
#686=FACE_BOUND('',#685,.T.);
#687=ADVANCED_FACE('F130',(#686),#668,.T.);
#688=CARTESIAN_POINT('',(26.9746669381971,53.6618279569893,55.));
#689=DIRECTION('',(0.,-1.,0.));
#690=DIRECTION('',(0.,0.,-1.));
#691=AXIS2_PLACEMENT_3D('',#688,#689,#690);
#692=CYLINDRICAL_SURFACE('',#691,5.);
#693=ORIENTED_EDGE('',*,*,#460,.F.);
#694=CARTESIAN_POINT('',(26.9746669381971,28.6618279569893,55.));
#695=DIRECTION('',(0.894427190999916,-0.447213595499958,0.));
#696=DIRECTION('',(-0.447213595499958,-0.894427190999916,0.));
#697=AXIS2_PLACEMENT_3D('',#694,#695,#696);
#698=ELLIPSE('',#697,11.1803398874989,5.);
#699=EDGE_CURVE('E211',#451,#512,#698,.F.);
#700=ORIENTED_EDGE('',*,*,#699,.T.);
#701=ORIENTED_EDGE('',*,*,#513,.F.);
#702=ORIENTED_EDGE('',*,*,#575,.F.);
#703=EDGE_LOOP('',(#693,#700,#701,#702));
#704=FACE_BOUND('',#703,.T.);
#705=ADVANCED_FACE('F132',(#704),#692,.T.);
#706=CARTESIAN_POINT('',(36.9746669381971,38.6618279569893,60.));
#707=DIRECTION('',(0.,0.,1.));
#708=DIRECTION('',(1.,0.,0.));
#709=AXIS2_PLACEMENT_3D('',#706,#707,#708);
#710=CYLINDRICAL_SURFACE('',#709,5.);
#711=ORIENTED_EDGE('',*,*,#521,.F.);
#712=CARTESIAN_POINT('',(36.9746669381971,38.6618279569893,55.));
#713=DIRECTION('',(0.,0.,-1.));
#714=DIRECTION('',(-1.,0.,0.));
#715=AXIS2_PLACEMENT_3D('',#712,#713,#714);
#716=CIRCLE('',#715,5.);
#717=EDGE_CURVE('E114',#306,#512,#716,.T.);
#718=ORIENTED_EDGE('',*,*,#717,.F.);
#719=ORIENTED_EDGE('',*,*,#307,.F.);
#720=ORIENTED_EDGE('',*,*,#559,.F.);
#721=EDGE_LOOP('',(#711,#718,#719,#720));
#722=FACE_BOUND('',#721,.T.);
#723=ADVANCED_FACE('F136',(#722),#710,.F.);
#724=CARTESIAN_POINT('',(96.1490143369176,38.6618279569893,22.1202496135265));
#725=DIRECTION('',(-1.,0.,0.));
#726=DIRECTION('',(0.,0.,1.));
#727=AXIS2_PLACEMENT_3D('',#724,#725,#726);
#728=CYLINDRICAL_SURFACE('',#727,5.);
#729=ORIENTED_EDGE('',*,*,#267,.F.);
#730=ORIENTED_EDGE('',*,*,#227,.F.);
#731=ORIENTED_EDGE('',*,*,#625,.F.);
#732=ORIENTED_EDGE('',*,*,#596,.F.);
#733=EDGE_LOOP('',(#729,#730,#731,#732));
#734=FACE_BOUND('',#733,.T.);
#735=ADVANCED_FACE('F100',(#734),#728,.F.);
#736=CARTESIAN_POINT('',(91.1490143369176,0.,12.1202496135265));
#737=DIRECTION('',(0.,-1.,0.));
#738=DIRECTION('',(0.,0.,-1.));
#739=AXIS2_PLACEMENT_3D('',#736,#737,#738);
#740=CYLINDRICAL_SURFACE('',#739,5.);
#741=ORIENTED_EDGE('',*,*,#633,.F.);
#742=ORIENTED_EDGE('',*,*,#243,.T.);
#743=ORIENTED_EDGE('',*,*,#407,.F.);
#744=ORIENTED_EDGE('',*,*,#656,.F.);
#745=EDGE_LOOP('',(#741,#742,#743,#744));
#746=FACE_BOUND('',#745,.T.);
#747=ADVANCED_FACE('F203',(#746),#740,.T.);
#748=CARTESIAN_POINT('',(91.1490143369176,28.6618279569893,60.));
#749=DIRECTION('',(0.,0.,-1.));
#750=DIRECTION('',(-1.,0.,0.));
#751=AXIS2_PLACEMENT_3D('',#748,#749,#750);
#752=CYLINDRICAL_SURFACE('',#751,5.);
#753=ORIENTED_EDGE('',*,*,#415,.F.);
#754=ORIENTED_EDGE('',*,*,#236,.T.);
#755=ORIENTED_EDGE('',*,*,#259,.F.);
#756=ORIENTED_EDGE('',*,*,#683,.F.);
#757=EDGE_LOOP('',(#753,#754,#755,#756));
#758=FACE_BOUND('',#757,.T.);
#759=ADVANCED_FACE('F110',(#758),#752,.T.);
#760=CARTESIAN_POINT('',(26.9746669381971,28.6618279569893,60.));
#761=CARTESIAN_POINT('',(26.9746669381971,28.6618279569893,60.));
#762=CARTESIAN_POINT('',(26.9746669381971,28.6618279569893,60.));
#763=CARTESIAN_POINT('',(27.0836006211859,28.8796953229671,59.9999937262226));
#764=CARTESIAN_POINT('',(27.1380671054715,28.8252281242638,60.000023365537));
#765=CARTESIAN_POINT('',(27.1925343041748,28.7707616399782,59.9999937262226));
#766=CARTESIAN_POINT('',(27.1925185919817,29.0975312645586,59.9964401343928));
#767=CARTESIAN_POINT('',(27.3015600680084,28.9887210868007,59.9928727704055));
#768=CARTESIAN_POINT('',(27.4103702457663,28.8796796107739,59.9964401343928));
#769=CARTESIAN_POINT('',(27.4101297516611,29.5327535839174,59.9821960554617));
#770=CARTESIAN_POINT('',(27.6272789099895,29.3144399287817,59.9644021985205));
#771=CARTESIAN_POINT('',(27.8455925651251,29.0972907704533,59.9821960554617));
#772=CARTESIAN_POINT('',(27.5188229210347,29.7501399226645,59.9715049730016));
#773=CARTESIAN_POINT('',(27.7897351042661,29.4768961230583,59.9430405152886));
#774=CARTESIAN_POINT('',(28.0629789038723,29.2059839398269,59.9715049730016));
#775=CARTESIAN_POINT('',(27.8423369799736,30.3971680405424,59.9289145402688));
#776=CARTESIAN_POINT('',(28.2714855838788,29.958646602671,59.8580783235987));
#777=CARTESIAN_POINT('',(28.7100070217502,29.5294979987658,59.9289145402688));
#778=CARTESIAN_POINT('',(28.0565186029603,30.8255312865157,59.8864982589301));
#779=CARTESIAN_POINT('',(28.5880472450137,30.2752082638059,59.7733272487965));
#780=CARTESIAN_POINT('',(29.1383702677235,29.7436796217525,59.8864982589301));
#781=CARTESIAN_POINT('',(28.4774457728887,31.6673856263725,59.7737138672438));
#782=CARTESIAN_POINT('',(29.1970078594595,30.8841688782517,59.55182076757));
#783=CARTESIAN_POINT('',(29.9802246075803,30.1646067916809,59.7737138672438));
#784=CARTESIAN_POINT('',(28.6842557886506,32.0810056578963,59.7038265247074));
#785=CARTESIAN_POINT('',(29.4912370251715,31.1783980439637,59.4147412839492));
#786=CARTESIAN_POINT('',(30.3938446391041,30.3714168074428,59.7038265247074));
#787=CARTESIAN_POINT('',(29.0868912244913,32.8862765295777,59.5370486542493));
#788=CARTESIAN_POINT('',(30.0448694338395,31.7320304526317,59.0954379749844));
#789=CARTESIAN_POINT('',(31.1991155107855,30.7740522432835,59.5370486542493));
#790=CARTESIAN_POINT('',(29.2828617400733,33.2782175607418,59.4408657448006));
#791=CARTESIAN_POINT('',(30.3060445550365,31.9932055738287,58.9127310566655));
#792=CARTESIAN_POINT('',(31.5910565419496,30.9700227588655,59.4408657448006));
#793=CARTESIAN_POINT('',(29.6603669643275,34.0332280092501,59.2229131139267));
#794=CARTESIAN_POINT('',(30.7835730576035,32.4707340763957,58.5125006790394));
#795=CARTESIAN_POINT('',(32.3460669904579,31.3475279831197,59.2229131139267));
#796=CARTESIAN_POINT('',(29.8421626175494,34.3968193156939,59.1020552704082));
#797=CARTESIAN_POINT('',(31.0015943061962,32.6887553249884,58.2943521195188));
#798=CARTESIAN_POINT('',(32.7096582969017,31.5293236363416,59.1020552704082));
#799=CARTESIAN_POINT('',(30.1880868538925,35.0886677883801,58.8366182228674));
#800=CARTESIAN_POINT('',(31.3844147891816,33.0715758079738,57.8377331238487));
#801=CARTESIAN_POINT('',(33.4015067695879,31.8752478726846,58.8366182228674));
#802=CARTESIAN_POINT('',(30.3526242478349,35.4177425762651,58.6931147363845));
#803=CARTESIAN_POINT('',(31.5507169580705,33.2378779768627,57.5985376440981));
#804=CARTESIAN_POINT('',(33.7305815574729,32.0397852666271,58.6931147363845));
#805=CARTESIAN_POINT('',(30.6610643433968,36.0346227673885,58.3846663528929));
#806=CARTESIAN_POINT('',(31.8247260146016,33.5118870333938,57.1189752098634));
#807=CARTESIAN_POINT('',(34.3474617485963,32.348225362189,58.3846663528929));
#808=CARTESIAN_POINT('',(30.805547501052,36.3235890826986,58.2208953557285));
#809=CARTESIAN_POINT('',(31.933706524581,33.6208675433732,56.8778590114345));
#810=CARTESIAN_POINT('',(34.6364280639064,32.4927085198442,58.2208953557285));
#811=CARTESIAN_POINT('',(31.0712119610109,36.8549180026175,57.8746787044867));
#812=CARTESIAN_POINT('',(32.0930741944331,33.7802352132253,56.4176770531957));
#813=CARTESIAN_POINT('',(35.1677569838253,32.7583729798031,57.8746787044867));
#814=CARTESIAN_POINT('',(31.1931487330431,37.0987915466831,57.6934033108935));
#815=CARTESIAN_POINT('',(32.1444569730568,33.831617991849,56.197946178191));
#816=CARTESIAN_POINT('',(35.4116305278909,32.8803097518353,57.6934033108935));
#817=CARTESIAN_POINT('',(31.4115084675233,37.53551101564,57.3151381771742));
#818=CARTESIAN_POINT('',(32.1967913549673,33.8839523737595,55.8049851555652));
#819=CARTESIAN_POINT('',(35.8483499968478,33.0986694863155,57.3151381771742));
#820=CARTESIAN_POINT('',(31.5088203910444,37.7301348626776,57.1191960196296));
#821=CARTESIAN_POINT('',(32.1984573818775,33.8856184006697,55.6312722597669));
#822=CARTESIAN_POINT('',(36.0429738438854,33.1959814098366,57.1191960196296));
#823=CARTESIAN_POINT('',(31.6350545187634,37.9826031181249,56.8144678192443));
#824=CARTESIAN_POINT('',(32.1771212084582,33.8642822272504,55.4189458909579));
#825=CARTESIAN_POINT('',(36.2954420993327,33.3222155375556,56.8144678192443));
#826=CARTESIAN_POINT('',(31.673254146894,38.0590023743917,56.7132440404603));
#827=CARTESIAN_POINT('',(32.1662581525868,33.853419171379,55.3566988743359));
#828=CARTESIAN_POINT('',(36.3718413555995,33.3604151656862,56.7132440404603));
#829=CARTESIAN_POINT('',(31.7435149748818,38.1995240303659,56.5066425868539));
#830=CARTESIAN_POINT('',(32.1396986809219,33.8268596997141,55.247580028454));
#831=CARTESIAN_POINT('',(36.5123630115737,33.430675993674,56.5066425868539));
#832=CARTESIAN_POINT('',(31.7755791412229,38.2636523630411,56.4012669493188));
#833=CARTESIAN_POINT('',(32.1239672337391,33.8111282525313,55.2009765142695));
#834=CARTESIAN_POINT('',(36.5764913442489,33.4627401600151,56.4012669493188));
#835=CARTESIAN_POINT('',(31.8321674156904,38.3768289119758,56.1900792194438));
#836=CARTESIAN_POINT('',(32.091369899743,33.7785309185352,55.1247541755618));
#837=CARTESIAN_POINT('',(36.6896678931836,33.5193284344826,56.1900792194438));
#838=CARTESIAN_POINT('',(31.8568857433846,38.4262655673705,56.0843713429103));
#839=CARTESIAN_POINT('',(32.0745625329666,33.7617235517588,55.0948941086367));
#840=CARTESIAN_POINT('',(36.7391045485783,33.5440467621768,56.0843713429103));
#841=CARTESIAN_POINT('',(31.899550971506,38.5115960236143,55.8702984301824));
#842=CARTESIAN_POINT('',(32.0426593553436,33.7298203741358,55.0487887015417));
#843=CARTESIAN_POINT('',(36.8244350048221,33.5867119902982,55.8702984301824));
#844=CARTESIAN_POINT('',(31.9175011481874,38.5474963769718,55.7619347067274));
#845=CARTESIAN_POINT('',(32.0276142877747,33.7147753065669,55.0327016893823));
#846=CARTESIAN_POINT('',(36.8603353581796,33.6046621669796,55.7619347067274));
#847=CARTESIAN_POINT('',(31.9460497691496,38.6045936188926,55.5450861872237));
#848=CARTESIAN_POINT('',(32.0023863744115,33.6895473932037,55.0111438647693));
#849=CARTESIAN_POINT('',(36.9174326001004,33.6332107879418,55.5450861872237));
#850=CARTESIAN_POINT('',(31.9567618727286,38.6260178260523,55.4366314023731));
#851=CARTESIAN_POINT('',(31.9921862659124,33.6793472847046,55.0055902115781));
#852=CARTESIAN_POINT('',(36.9388568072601,33.6439228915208,55.4366314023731));
#853=CARTESIAN_POINT('',(31.9710703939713,38.6546348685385,55.2187844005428));
#854=CARTESIAN_POINT('',(31.9783075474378,33.66546856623,55.000008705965));
#855=CARTESIAN_POINT('',(36.9674738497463,33.6582314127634,55.2187844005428));
#856=CARTESIAN_POINT('',(31.9746669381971,38.6618279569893,55.1093922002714));
#857=CARTESIAN_POINT('',(31.9746669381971,33.6618279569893,55.0000043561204));
#858=CARTESIAN_POINT('',(36.9746669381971,33.6618279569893,55.1093922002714));
#859=CARTESIAN_POINT('',(31.9746669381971,38.6618279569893,54.8906077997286));
#860=CARTESIAN_POINT('',(31.9746669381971,33.6618279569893,54.9999956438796));
#861=CARTESIAN_POINT('',(36.9746669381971,33.6618279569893,54.8906077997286));
#862=CARTESIAN_POINT('',(31.9710703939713,38.6546348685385,54.7812155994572));
#863=CARTESIAN_POINT('',(31.9783075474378,33.66546856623,54.999991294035));
#864=CARTESIAN_POINT('',(36.9674738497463,33.6582314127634,54.7812155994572));
#865=CARTESIAN_POINT('',(31.9567618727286,38.6260178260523,54.5633685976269));
#866=CARTESIAN_POINT('',(31.9921862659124,33.6793472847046,54.994409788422));
#867=CARTESIAN_POINT('',(36.9388568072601,33.6439228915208,54.5633685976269));
#868=CARTESIAN_POINT('',(31.9460497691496,38.6045936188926,54.4549138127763));
#869=CARTESIAN_POINT('',(32.0023863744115,33.6895473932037,54.9888561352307));
#870=CARTESIAN_POINT('',(36.9174326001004,33.6332107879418,54.4549138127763));
#871=CARTESIAN_POINT('',(31.9175011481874,38.5474963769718,54.2380652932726));
#872=CARTESIAN_POINT('',(32.0276142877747,33.7147753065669,54.9672983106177));
#873=CARTESIAN_POINT('',(36.8603353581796,33.6046621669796,54.2380652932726));
#874=CARTESIAN_POINT('',(31.899550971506,38.5115960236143,54.1297015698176));
#875=CARTESIAN_POINT('',(32.0426593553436,33.7298203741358,54.9512112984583));
#876=CARTESIAN_POINT('',(36.8244350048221,33.5867119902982,54.1297015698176));
#877=CARTESIAN_POINT('',(31.8568857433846,38.4262655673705,53.9156286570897));
#878=CARTESIAN_POINT('',(32.0745625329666,33.7617235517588,54.9051058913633));
#879=CARTESIAN_POINT('',(36.7391045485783,33.5440467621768,53.9156286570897));
#880=CARTESIAN_POINT('',(31.8321674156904,38.3768289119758,53.8099207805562));
#881=CARTESIAN_POINT('',(32.091369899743,33.7785309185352,54.8752458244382));
#882=CARTESIAN_POINT('',(36.6896678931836,33.5193284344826,53.8099207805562));
#883=CARTESIAN_POINT('',(31.7755791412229,38.2636523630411,53.5987330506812));
#884=CARTESIAN_POINT('',(32.1239672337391,33.8111282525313,54.7990234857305));
#885=CARTESIAN_POINT('',(36.5764913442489,33.4627401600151,53.5987330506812));
#886=CARTESIAN_POINT('',(31.7435149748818,38.1995240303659,53.4933574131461));
#887=CARTESIAN_POINT('',(32.1396986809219,33.8268596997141,54.7524199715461));
#888=CARTESIAN_POINT('',(36.5123630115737,33.430675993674,53.4933574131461));
#889=CARTESIAN_POINT('',(31.673254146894,38.0590023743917,53.2867559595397));
#890=CARTESIAN_POINT('',(32.1662581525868,33.853419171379,54.6433011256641));
#891=CARTESIAN_POINT('',(36.3718413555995,33.3604151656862,53.2867559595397));
#892=CARTESIAN_POINT('',(31.6350545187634,37.9826031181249,53.1855321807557));
#893=CARTESIAN_POINT('',(32.1771212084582,33.8642822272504,54.5810541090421));
#894=CARTESIAN_POINT('',(36.2954420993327,33.3222155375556,53.1855321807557));
#895=CARTESIAN_POINT('',(31.5088203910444,37.7301348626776,52.8808039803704));
#896=CARTESIAN_POINT('',(32.1984573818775,33.8856184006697,54.3687277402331));
#897=CARTESIAN_POINT('',(36.0429738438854,33.1959814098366,52.8808039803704));
#898=CARTESIAN_POINT('',(31.4115084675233,37.53551101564,52.6848618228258));
#899=CARTESIAN_POINT('',(32.1967913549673,33.8839523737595,54.1950148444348));
#900=CARTESIAN_POINT('',(35.8483499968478,33.0986694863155,52.6848618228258));
#901=CARTESIAN_POINT('',(31.1931487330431,37.0987915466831,52.3065966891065));
#902=CARTESIAN_POINT('',(32.1444569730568,33.831617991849,53.802053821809));
#903=CARTESIAN_POINT('',(35.4116305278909,32.8803097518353,52.3065966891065));
#904=CARTESIAN_POINT('',(31.0712119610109,36.8549180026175,52.1253212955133));
#905=CARTESIAN_POINT('',(32.0930741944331,33.7802352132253,53.5823229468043));
#906=CARTESIAN_POINT('',(35.1677569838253,32.7583729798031,52.1253212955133));
#907=CARTESIAN_POINT('',(30.805547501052,36.3235890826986,51.7791046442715));
#908=CARTESIAN_POINT('',(31.933706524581,33.6208675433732,53.1221409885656));
#909=CARTESIAN_POINT('',(34.6364280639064,32.4927085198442,51.7791046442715));
#910=CARTESIAN_POINT('',(30.6610643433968,36.0346227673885,51.6153336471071));
#911=CARTESIAN_POINT('',(31.8247260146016,33.5118870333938,52.8810247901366));
#912=CARTESIAN_POINT('',(34.3474617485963,32.348225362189,51.6153336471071));
#913=CARTESIAN_POINT('',(30.3526242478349,35.4177425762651,51.3068852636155));
#914=CARTESIAN_POINT('',(31.5507169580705,33.2378779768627,52.4014623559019));
#915=CARTESIAN_POINT('',(33.7305815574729,32.0397852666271,51.3068852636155));
#916=CARTESIAN_POINT('',(30.1880868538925,35.0886677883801,51.1633817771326));
#917=CARTESIAN_POINT('',(31.3844147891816,33.0715758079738,52.1622668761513));
#918=CARTESIAN_POINT('',(33.4015067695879,31.8752478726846,51.1633817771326));
#919=CARTESIAN_POINT('',(29.8421626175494,34.3968193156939,50.8979447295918));
#920=CARTESIAN_POINT('',(31.0015943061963,32.6887553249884,51.7056478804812));
#921=CARTESIAN_POINT('',(32.7096582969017,31.5293236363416,50.8979447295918));
#922=CARTESIAN_POINT('',(29.6603669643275,34.0332280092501,50.7770868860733));
#923=CARTESIAN_POINT('',(30.7835730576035,32.4707340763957,51.4874993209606));
#924=CARTESIAN_POINT('',(32.3460669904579,31.3475279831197,50.7770868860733));
#925=CARTESIAN_POINT('',(29.2828617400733,33.2782175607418,50.5591342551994));
#926=CARTESIAN_POINT('',(30.3060445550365,31.9932055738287,51.0872689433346));
#927=CARTESIAN_POINT('',(31.5910565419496,30.9700227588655,50.5591342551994));
#928=CARTESIAN_POINT('',(29.0868912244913,32.8862765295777,50.4629513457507));
#929=CARTESIAN_POINT('',(30.0448694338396,31.7320304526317,50.9045620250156));
#930=CARTESIAN_POINT('',(31.1991155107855,30.7740522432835,50.4629513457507));
#931=CARTESIAN_POINT('',(28.6842557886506,32.0810056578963,50.2961734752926));
#932=CARTESIAN_POINT('',(29.4912370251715,31.1783980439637,50.5852587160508));
#933=CARTESIAN_POINT('',(30.3938446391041,30.3714168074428,50.2961734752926));
#934=CARTESIAN_POINT('',(28.4774457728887,31.6673856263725,50.2262861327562));
#935=CARTESIAN_POINT('',(29.1970078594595,30.8841688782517,50.44817923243));
#936=CARTESIAN_POINT('',(29.9802246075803,30.1646067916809,50.2262861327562));
#937=CARTESIAN_POINT('',(28.0565186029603,30.8255312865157,50.1135017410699));
#938=CARTESIAN_POINT('',(28.5880472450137,30.2752082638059,50.2266727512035));
#939=CARTESIAN_POINT('',(29.1383702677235,29.7436796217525,50.1135017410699));
#940=CARTESIAN_POINT('',(27.8423369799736,30.3971680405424,50.0710854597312));
#941=CARTESIAN_POINT('',(28.2714855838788,29.958646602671,50.1419216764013));
#942=CARTESIAN_POINT('',(28.7100070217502,29.5294979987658,50.0710854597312));
#943=CARTESIAN_POINT('',(27.5188229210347,29.7501399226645,50.0284950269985));
#944=CARTESIAN_POINT('',(27.7897351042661,29.4768961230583,50.0569594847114));
#945=CARTESIAN_POINT('',(28.0629789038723,29.2059839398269,50.0284950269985));
#946=CARTESIAN_POINT('',(27.4101297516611,29.5327535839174,50.0178039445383));
#947=CARTESIAN_POINT('',(27.6272789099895,29.3144399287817,50.0355978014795));
#948=CARTESIAN_POINT('',(27.8455925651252,29.0972907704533,50.0178039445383));
#949=CARTESIAN_POINT('',(27.1925185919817,29.0975312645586,50.0035598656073));
#950=CARTESIAN_POINT('',(27.3015600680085,28.9887210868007,50.0071272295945));
#951=CARTESIAN_POINT('',(27.4103702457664,28.8796796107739,50.0035598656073));
#952=CARTESIAN_POINT('',(27.0836006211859,28.879695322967,50.0000062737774));
#953=CARTESIAN_POINT('',(27.1380671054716,28.8252281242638,49.9999766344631));
#954=CARTESIAN_POINT('',(27.1925343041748,28.7707616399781,50.0000062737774));
#955=CARTESIAN_POINT('',(26.9746669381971,28.6618279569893,50.));
#956=CARTESIAN_POINT('',(26.9746669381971,28.6618279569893,50.));
#957=CARTESIAN_POINT('',(26.9746669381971,28.6618279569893,50.));
#958=(BOUNDED_SURFACE() B_SPLINE_SURFACE(3,2,((#760,#761,#762),(#763,#764,#765),(#766,#767,
#768),(#769,#770,#771),(#772,#773,#774),(#775,#776,#777),(#778,#779,#780),(#781,#782,#783),
(#784,#785,#786),(#787,#788,#789),(#790,#791,#792),(#793,#794,#795),(#796,#797,#798),(#799,#800,
#801),(#802,#803,#804),(#805,#806,#807),(#808,#809,#810),(#811,#812,#813),(#814,#815,#816),
(#817,#818,#819),(#820,#821,#822),(#823,#824,#825),(#826,#827,#828),(#829,#830,#831),(#832,#833,
#834),(#835,#836,#837),(#838,#839,#840),(#841,#842,#843),(#844,#845,#846),(#847,#848,#849),
(#850,#851,#852),(#853,#854,#855),(#856,#857,#858),(#859,#860,#861),(#862,#863,#864),(#865,#866,
#867),(#868,#869,#870),(#871,#872,#873),(#874,#875,#876),(#877,#878,#879),(#880,#881,#882),
(#883,#884,#885),(#886,#887,#888),(#889,#890,#891),(#892,#893,#894),(#895,#896,#897),(#898,#899,
#900),(#901,#902,#903),(#904,#905,#906),(#907,#908,#909),(#910,#911,#912),(#913,#914,#915),
(#916,#917,#918),(#919,#920,#921),(#922,#923,#924),(#925,#926,#927),(#928,#929,#930),(#931,#932,
#933),(#934,#935,#936),(#937,#938,#939),(#940,#941,#942),(#943,#944,#945),(#946,#947,#948),
(#949,#950,#951),(#952,#953,#954),(#955,#956,#957)),.UNSPECIFIED.,.F.,.F.,
.F.) B_SPLINE_SURFACE_WITH_KNOTS((4,2,2,2,2,2,2,2,2,2,2,2,2,2,2,2,2,2,2,2,2,2,2,2,2,2,2,2,2,2,2,
2,4),(3,3),(0.,0.924160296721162,1.84839768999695,3.68059127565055,5.48205356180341,
7.23913791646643,8.94029416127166,10.5768174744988,12.1436214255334,13.6400005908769,
15.0702934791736,15.7580538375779,16.4454808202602,17.1126662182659,17.7795282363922,
18.4356587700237,19.0917776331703,19.7478964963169,20.4040270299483,21.0708890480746,
21.7380744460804,22.4255014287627,23.1132617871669,24.5435546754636,26.0399338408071,
27.6067377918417,29.2432611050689,30.9444173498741,32.7015017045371,34.50296399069,
36.3351575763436,37.2593949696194,38.1835552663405),(0.,1.),
.UNSPECIFIED.) GEOMETRIC_REPRESENTATION_ITEM() RATIONAL_B_SPLINE_SURFACE(((1.,1.,1.),(1.,
0.999999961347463,1.),(1.,0.999643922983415,1.),(1.,0.998220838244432,1.),(1.,0.9971537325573,
1.),(1.,0.992912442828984,1.),(1.,0.988698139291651,1.),(1.,0.97761667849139,1.),(1.,
0.970795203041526,1.),(1.,0.954789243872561,1.),(1.,0.945667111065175,1.),(1.,0.925487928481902,
1.),(1.,0.914501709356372,1.),(1.,0.891170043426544,1.),(1.,0.878892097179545,1.),(1.,
0.853706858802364,1.),(1.,0.840848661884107,1.),(1.,0.815387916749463,1.),(1.,0.802799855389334,
1.),(1.,0.778879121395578,1.),(1.,0.767515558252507,1.),(1.,0.752114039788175,1.),(1.,
0.747335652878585,1.),(1.,0.738380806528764,1.),(1.,0.734204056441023,1.),(1.,0.726720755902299,
1.),(1.,0.723392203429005,1.),(1.,0.717584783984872,1.),(1.,0.715105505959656,1.),(1.,
0.711136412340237,1.),(1.,0.709631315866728,1.),(1.,0.70761650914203,1.),(1.,0.707106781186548,
1.),(1.,0.707106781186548,1.),(1.,0.70761650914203,1.),(1.,0.709631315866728,1.),(1.,
0.711136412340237,1.),(1.,0.715105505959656,1.),(1.,0.717584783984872,1.),(1.,0.723392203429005,
1.),(1.,0.726720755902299,1.),(1.,0.734204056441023,1.),(1.,0.738380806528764,1.),(1.,
0.747335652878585,1.),(1.,0.752114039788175,1.),(1.,0.767515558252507,1.),(1.,0.778879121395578,
1.),(1.,0.802799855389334,1.),(1.,0.815387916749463,1.),(1.,0.840848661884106,1.),(1.,
0.853706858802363,1.),(1.,0.878892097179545,1.),(1.,0.891170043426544,1.),(1.,0.914501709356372,
1.),(1.,0.925487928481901,1.),(1.,0.945667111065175,1.),(1.,0.954789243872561,1.),(1.,
0.970795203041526,1.),(1.,0.97761667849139,1.),(1.,0.988698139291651,1.),(1.,0.992912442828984,
1.),(1.,0.9971537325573,1.),(1.,0.998220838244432,1.),(1.,0.999643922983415,1.),(1.,
0.999999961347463,1.),(1.,1.,1.))) REPRESENTATION_ITEM('') SURFACE());
#959=ORIENTED_EDGE('',*,*,#717,.T.);
#960=ORIENTED_EDGE('',*,*,#699,.F.);
#961=ORIENTED_EDGE('',*,*,#675,.F.);
#962=EDGE_LOOP('',(#959,#960,#961));
#963=FACE_BOUND('',#962,.T.);
#964=ADVANCED_FACE('F122',(#963),#958,.F.);
#965=CLOSED_SHELL('',(#247,#317,#364,#395,#440,#473,#499,#539,#563,#582,#615,#644,#663,#687,
#705,#723,#735,#747,#759,#964));
#966=MANIFOLD_SOLID_BREP('B2',#965);
#967=ADVANCED_BREP_SHAPE_REPRESENTATION('',(#18,#966),#14);
#968=SHAPE_DEFINITION_REPRESENTATION(#9,#967);
ENDSEC;
END-ISO-10303-21;
